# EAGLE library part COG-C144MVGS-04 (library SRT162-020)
1.5 inch LCD

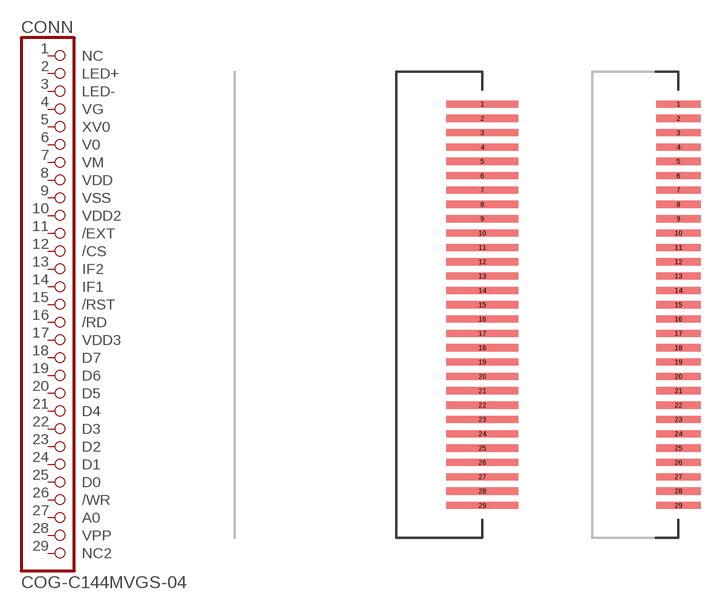
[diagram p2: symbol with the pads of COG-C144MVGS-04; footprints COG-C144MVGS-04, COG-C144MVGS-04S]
Designator prefix CONN

## COG-C144MVGS-04  [COG-C144MVGS-04]
1  NC  pas
2  LED+  pas
3  LED-  pas
4  VG  pas
5  XV0  pas
6  V0  pas
7  VM  pas
8  VDD  in
9  VSS  pas
10  VDD2  in
11  /EXT  pas
12  /CS  in
13  IF2  in
14  IF1  in
15  /RST  in
16  /RD  in
17  VDD3  in
18  D7
19  D6
20  D5
21  D4
22  D3
23  D2
24  D1
25  D0
26  /WR  in
27  A0  in
28  VPP  pas
29  NC2  pas

## COG-C144MVGS-04S  [COG-C144MVGS-04S]
1  NC  pas
2  LED-  pas
3  LED+  pas
4  VG  pas
5  XV0  pas
6  V0  pas
7  VM  pas
8  VDD  in
9  VSS  pas
10  VDD2  in
11  /EXT  pas
12  /CS  in
13  IF2  in
14  IF1  in
15  /RST  in
16  /RD  in
17  VDD3  in
18  D7
19  D6
20  D5
21  D4
22  D3
23  D2
24  D1
25  D0
26  /WR  in
27  A0  in
28  VPP  pas
29  NC2  pas

## Footprint COG-C144MVGS-04 (pad centres in mm)
COG-C144MVGS-04 : 1.5 inch LCD module
smd 4 x 0.4: 1 0,11.2; 2 0,10.4; 3 0,9.6; 4 0,8.8; 5 0,8; 6 0,7.2; 7 0,6.4; 8 0,5.6; 9 0,4.8; 10 0,4; 11 0,3.2; 12 0,2.4; 13 0,1.6; 14 0,0.8; 15 0,0; 16 0,-0.8; 17 0,-1.6; 18 0,-2.4; 19 0,-3.2; 20 0,-4; 21 0,-4.8; 22 0,-5.6; 23 0,-6.4; 24 0,-7.2; 25 0,-8; 26 0,-8.8; 27 0,-9.6; 28 0,-10.4; 29 0,-11.2

## Footprint COG-C144MVGS-04S (pad centres in mm)
smd 2.5 x 0.4: 1 0,11.2; 2 0,10.4; 3 0,9.6; 4 0,8.8; 5 0,8; 6 0,7.2; 7 0,6.4; 8 0,5.6; 9 0,4.8; 10 0,4; 11 0,3.2; 12 0,2.4; 13 0,1.6; 14 0,0.8; 15 0,0; 16 0,-0.8; 17 0,-1.6; 18 0,-2.4; 19 0,-3.2; 20 0,-4; 21 0,-4.8; 22 0,-5.6; 23 0,-6.4; 24 0,-7.2; 25 0,-8; 26 0,-8.8; 27 0,-9.6; 28 0,-10.4; 29 0,-11.2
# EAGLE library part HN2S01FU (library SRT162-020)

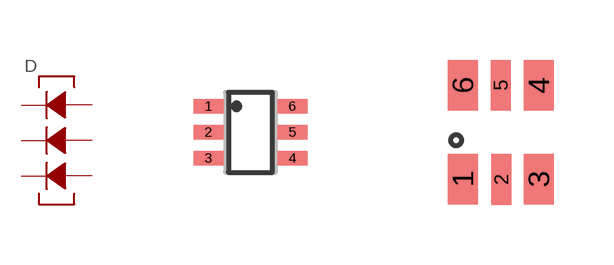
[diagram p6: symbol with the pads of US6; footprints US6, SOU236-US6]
Designator prefix D

## HN2S01FU  [US6]
1  1  pas
2  2  pas
3  3  pas
4  4  pas
5  5  pas
6  6  pas

## HN2S01FUL  [SOU236-US6]
Pads as for US6

## Footprint US6 (pad centres in mm)
0.65 mm pitch narrow (1.25 mm) width package
smd 0.762 x 0.356: 1 -1.05,0.65; 2 -1.05,0; 3 -1.05,-0.65; 4 1.05,-0.65; 5 1.05,0; 6 1.05,0.65

## Footprint SOU236-US6 (pad centres in mm)
smd 0.762 x 1.27: 1 -0.95,-1.175; 3 0.95,-1.175; 4 0.95,1.175; 6 -0.95,1.175
smd 0.508 x 1.27: 2 0.013,-1.185; 5 0,1.175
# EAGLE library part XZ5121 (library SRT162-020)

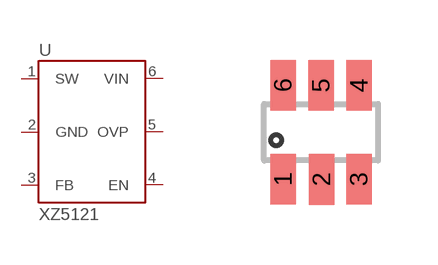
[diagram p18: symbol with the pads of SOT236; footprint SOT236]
Designator prefix U

## XZ5121  [SOT236]
1  SW  pas
2  GND  pwr
3  FB  in
4  EN  in
5  OVP  in
6  VIN  in

## Footprint SOT236 (pad centres in mm)
smd 0.635 x 1.27: 1 -0.95,-1.175; 2 0.013,-1.185; 3 0.95,-1.175; 4 0.95,1.175; 5 0,1.175; 6 -0.95,1.175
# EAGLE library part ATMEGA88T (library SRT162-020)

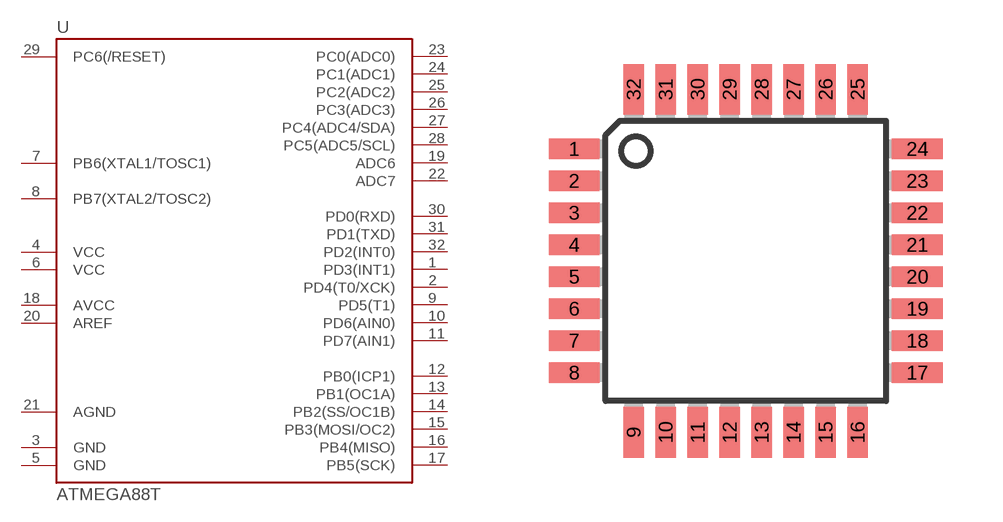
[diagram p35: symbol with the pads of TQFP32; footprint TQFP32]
Designator prefix U

## ATMEGA88T  [TQFP32]
1  PD3(INT1)
2  PD4(T0/XCK)
3  GND  pwr
4  VCC  pwr
5  GND  pwr
6  VCC  pwr
7  PB6(XTAL1/TOSC1)
8  PB7(XTAL2/TOSC2)
9  PD5(T1)
10  PD6(AIN0)
11  PD7(AIN1)
12  PB0(ICP1)
13  PB1(OC1A)
14  PB2(SS/OC1B)
15  PB3(MOSI/OC2)
16  PB4(MISO)
17  PB5(SCK)
18  AVCC  pas
19  ADC6  pas
20  AREF  pas
21  AGND  pwr
22  ADC7  pas
23  PC0(ADC0)
24  PC1(ADC1)
25  PC2(ADC2)
26  PC3(ADC3)
27  PC4(ADC4/SDA)
28  PC5(ADC5/SCL)
29  PC6(/RESET)
30  PD0(RXD)
31  PD1(TXD)
32  PD2(INT0)

## Footprint TQFP32 (pad centres in mm)
smd 1.27 x 0.508: 1 -4.293,2.8; 2 -4.293,2; 3 -4.293,1.2; 4 -4.293,0.4; 5 -4.293,-0.4; 6 -4.293,-1.2; 7 -4.293,-2; 8 -4.293,-2.8; 17 4.293,-2.8; 18 4.293,-2; 19 4.293,-1.2; 20 4.293,-0.4; 21 4.293,0.4; 22 4.293,1.2; 23 4.293,2; 24 4.293,2.8
smd 0.508 x 1.27: 9 -2.8,-4.293; 10 -2,-4.293; 11 -1.2,-4.293; 12 -0.4,-4.293; 13 0.4,-4.293; 14 1.2,-4.293; 15 2,-4.293; 16 2.8,-4.293; 25 2.8,4.293; 26 2,4.293; 27 1.2,4.293; 28 0.4,4.293; 29 -0.4,4.293; 30 -1.2,4.293; 31 -2,4.293; 32 -2.8,4.293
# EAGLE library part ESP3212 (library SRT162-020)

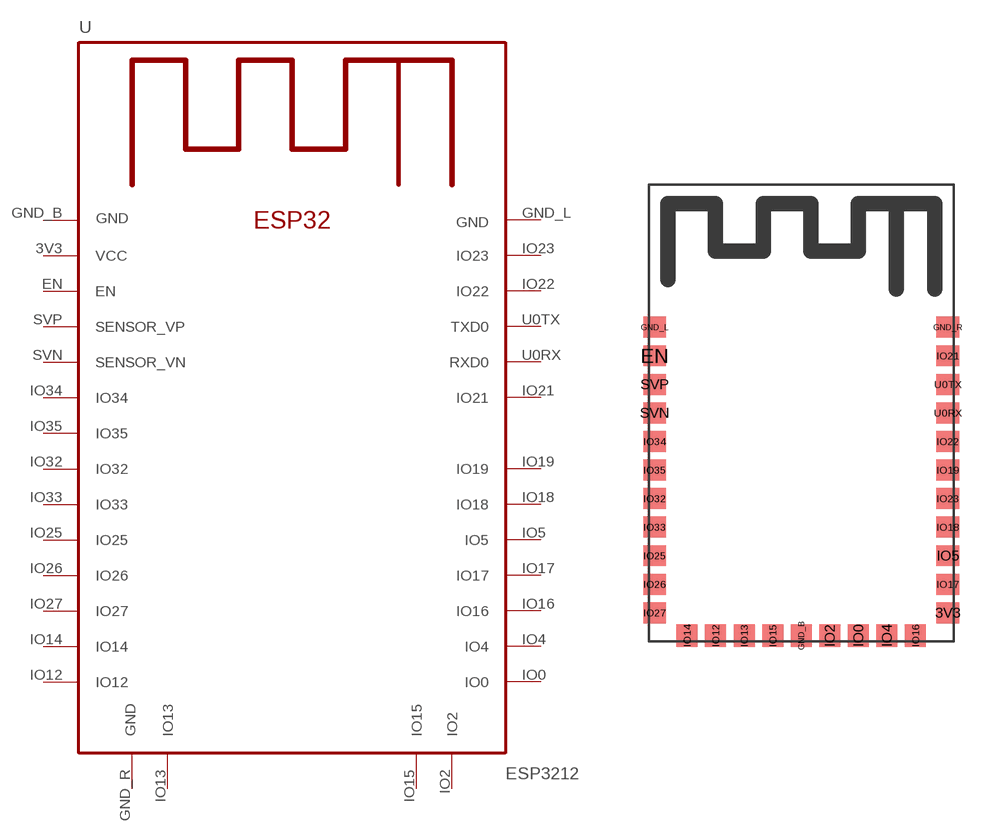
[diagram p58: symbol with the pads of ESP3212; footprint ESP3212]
Designator prefix U

## ESP3212  [ESP3212]
3V3  VCC  pwr
EN  EN
GND_B  GND  pwr
GND_L  GND  pwr
GND_R  GND  pwr
IO0  IO0
IO2  IO2
IO4  IO4
IO5  IO5
IO12  IO12
IO13  IO13
IO14  IO14
IO15  IO15
IO16  IO16
IO17  IO17
IO18  IO18
IO19  IO19
IO21  IO21
IO22  IO22
IO23  IO23
IO25  IO25
IO26  IO26
IO27  IO27
IO32  IO32
IO33  IO33
IO34  IO34
IO35  IO35
SVN  SENSOR_VN
SVP  SENSOR_VP
U0RX  RXD0
U0TX  TXD0

## Footprint ESP3212 (pad centres in mm)
smd 1.2 x 1.1: 3V3 8.08,-7.39; EN -7.32,6.11; GND_L -7.32,7.61; GND_R 8.08,7.61; IO5 8.08,-4.39; IO17 8.08,-5.89; IO18 8.08,-2.89; IO19 8.08,0.11; IO21 8.08,6.11; IO22 8.08,1.61; IO23 8.08,-1.39; IO25 -7.32,-4.39; IO26 -7.32,-5.89; IO27 -7.32,-7.39; IO32 -7.32,-1.39; IO33 -7.32,-2.89; IO34 -7.32,1.61; IO35 -7.32,0.11; SVN -7.32,3.11; SVP -7.32,4.61; U0RX 8.08,3.11; U0TX 8.08,4.61
smd 1.1 x 1.2: GND_B 0.38,-8.59; IO0 3.38,-8.59; IO2 1.88,-8.59; IO4 4.88,-8.59; IO12 -4.12,-8.59; IO13 -2.62,-8.59; IO14 -5.62,-8.59; IO15 -1.12,-8.59; IO16 6.38,-8.59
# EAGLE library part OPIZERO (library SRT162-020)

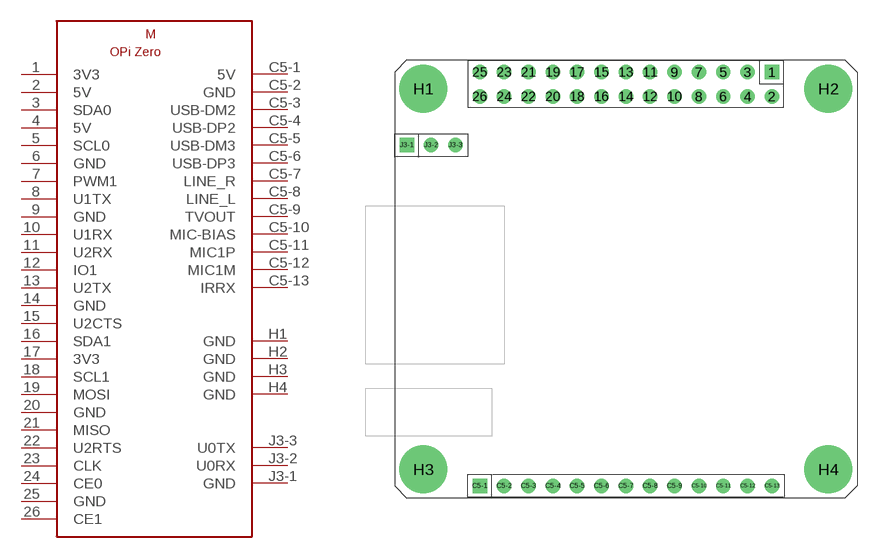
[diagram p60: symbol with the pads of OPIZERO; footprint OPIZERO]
Designator prefix M

## OPIZERO  [OPIZERO]
1  3V3
2  5V  pwr
3  SDA0
4  5V  pwr
5  SCL0
6  GND  pwr
7  PWM1
8  U1TX
9  GND  pwr
10  U1RX
11  U2RX
12  IO1
13  U2TX
14  GND  pwr
15  U2CTS
16  SDA1
17  3V3
18  SCL1
19  MOSI
20  GND  pwr
21  MISO
22  U2RTS
23  CLK
24  CE0
25  GND  pwr
26  CE1
C5-1  5V  pwr
C5-2  GND  pwr
C5-3  USB-DM2
C5-4  USB-DP2
C5-5  USB-DM3
C5-6  USB-DP3
C5-7  LINE_R
C5-8  LINE_L
C5-9  TVOUT
C5-10  MIC-BIAS
C5-11  MIC1P
C5-12  MIC1M
C5-13  IRRX
H1  GND  pwr
H2  GND  pwr
H3  GND  pwr
H4  GND  pwr
J3-1  GND  pwr
J3-2  U0RX
J3-3  U0TX

## Footprint OPIZERO (pad centres in mm)
drill 1 square: 1 15.24,22.86; C5-1 -15.24,-20.32; J3-1 -22.86,15.24
drill 1: 2 15.24,20.32; 3 12.7,22.86; 4 12.7,20.32; 5 10.16,22.86; 6 10.16,20.32; 7 7.62,22.86; 8 7.62,20.32; 9 5.08,22.86; 10 5.08,20.32; 11 2.54,22.86; 12 2.54,20.32; 13 0,22.86; 14 0,20.32; 15 -2.54,22.86; 16 -2.54,20.32; 17 -5.08,22.86; 18 -5.08,20.32; 19 -7.62,22.86; 20 -7.62,20.32; 21 -10.16,22.86; 22 -10.16,20.32; 23 -12.7,22.86; 24 -12.7,20.32; 25 -15.24,22.86; 26 -15.24,20.32; C5-2 -12.7,-20.32; C5-3 -10.16,-20.32; C5-4 -7.62,-20.32; C5-5 -5.08,-20.32; C5-6 -2.54,-20.32; C5-7 0,-20.32; C5-8 2.54,-20.32; C5-9 5.08,-20.32; C5-10 7.62,-20.32; C5-11 10.16,-20.32; C5-12 12.7,-20.32; C5-13 15.24,-20.32; J3-2 -20.32,15.24; J3-3 -17.78,15.24
drill 3.3 pad 5: H1 -21.13,21.13; H2 21.13,21.13; H3 -21.13,-18.59; H4 21.13,-18.59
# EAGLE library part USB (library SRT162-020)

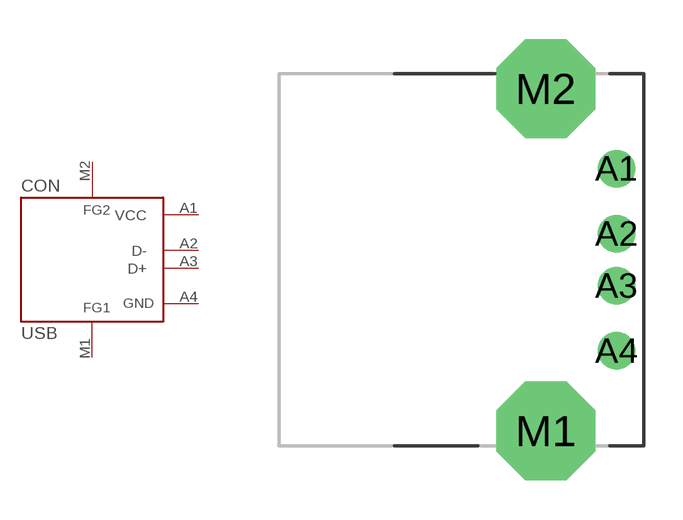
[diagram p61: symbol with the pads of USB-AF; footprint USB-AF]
Designator prefix CON

## USB-B  [USB-AF]
A1  VCC  pwr
A2  D-
A3  D+
A4  GND  pwr
M1  GND  pwr
M2  GND  pwr

## Footprint USB-AF (pad centres in mm)
drill 0.93: A1 3.175,3.5; A2 3.175,1; A3 3.175,-1; A4 3.175,-3.5
drill 2.4 pad 3.81 octagon: M1 0.465,-6.57; M2 0.465,6.57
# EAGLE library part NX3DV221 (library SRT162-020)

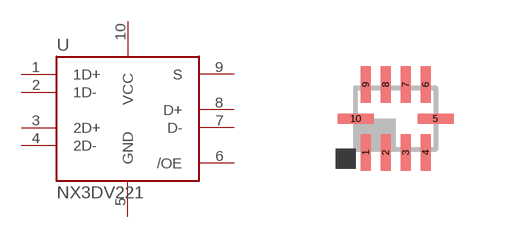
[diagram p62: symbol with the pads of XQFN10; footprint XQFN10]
Designator prefix -

## NX3DV221  [XQFN10]
1  1D+
2  1D-
3  2D+
4  2D-
5  GND  pwr
6  /OE
7  D-
8  D+
9  S
10  VCC  in

## Footprint XQFN10 (pad centres in mm)
smd 0.25 x 0.9: 1 -0.75,-0.85; 2 -0.25,-0.85; 3 0.25,-0.85; 4 0.75,-0.85; 6 0.75,0.85; 7 0.25,0.85; 8 -0.25,0.85; 9 -0.75,0.85
smd 0.9 x 0.25: 5 1,0; 10 -1,0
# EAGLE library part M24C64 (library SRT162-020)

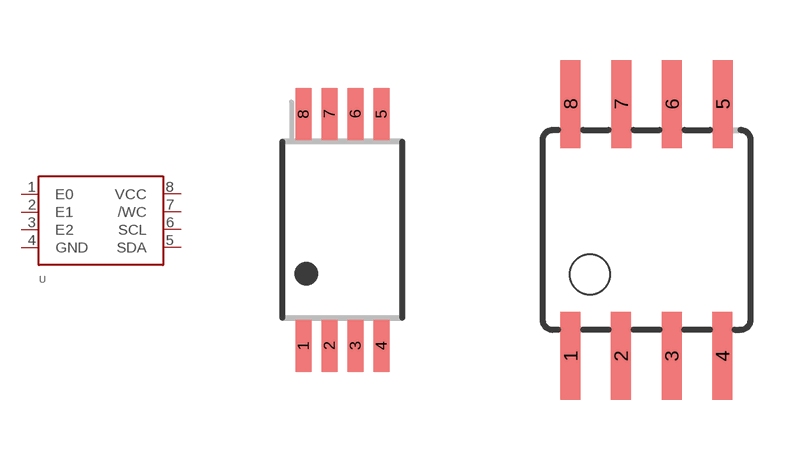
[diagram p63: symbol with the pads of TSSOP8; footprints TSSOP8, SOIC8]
Designator prefix -

## M24C64-DW  [TSSOP8]
1  E0  in
2  E1  in
3  E2  in
4  GND  pwr
5  SDA
6  SCL
7  /WC
8  VCC  pwr

## M24C64  [SOIC8]
Pads as for TSSOP8

## Footprint TSSOP8 (pad centres in mm)
smd 0.4 x 1.3: 1 -0.975,-2.9; 2 -0.325,-2.9; 3 0.325,-2.9; 4 0.975,-2.9; 5 0.975,2.9; 6 0.325,2.9; 7 -0.325,2.9; 8 -0.975,2.9

## Footprint SOIC8 (pad centres in mm)
smd 0.5 x 2.2: 1 -1.905,-3.154; 2 -0.645,-3.154; 3 0.625,-3.154; 4 1.895,-3.154; 5 1.905,3.154; 6 0.635,3.154; 7 -0.635,3.154; 8 -1.905,3.154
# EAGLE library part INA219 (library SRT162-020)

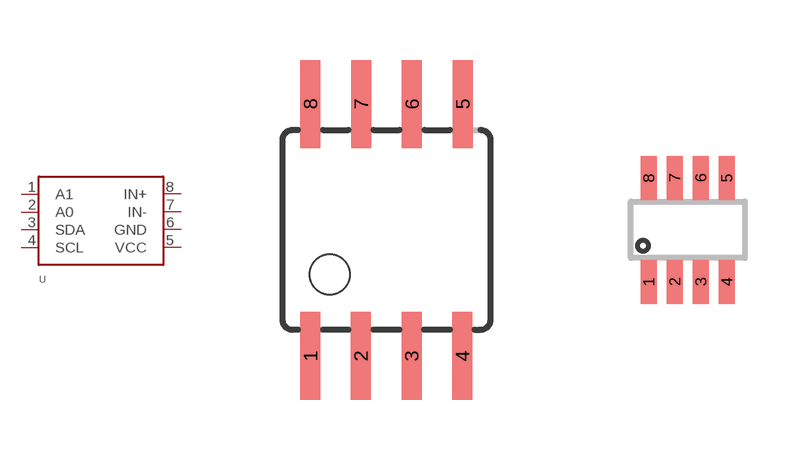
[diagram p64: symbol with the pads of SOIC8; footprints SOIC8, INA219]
Designator prefix -

## INA219SOP8  [SOIC8]
1  A1  in
2  A0  in
3  SDA
4  SCL
5  VCC  pwr
6  GND  pwr
7  IN-
8  IN+

## INA219SOT23-8  [INA219]
Pads as for SOIC8

## Footprint SOIC8 (pad centres in mm)
smd 0.5 x 2.2: 1 -1.905,-3.154; 2 -0.645,-3.154; 3 0.625,-3.154; 4 1.895,-3.154; 5 1.905,3.154; 6 0.635,3.154; 7 -0.635,3.154; 8 -1.905,3.154

## Footprint INA219 (pad centres in mm)
smd 0.4 x 1.1: 1 -0.975,-1.3; 2 -0.325,-1.3; 3 0.325,-1.3; 4 0.975,-1.3; 5 0.975,1.3; 6 0.325,1.3; 7 -0.325,1.3; 8 -0.975,1.3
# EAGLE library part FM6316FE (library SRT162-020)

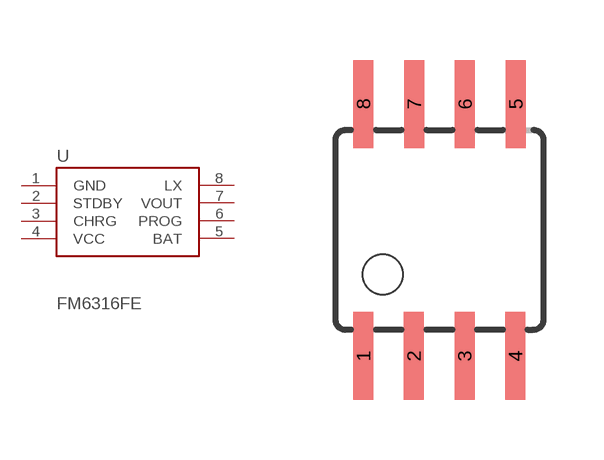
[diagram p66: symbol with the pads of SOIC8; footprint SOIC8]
Designator prefix -

## FM6316FE  [SOIC8]
1  GND  pwr
2  STDBY
3  CHRG
4  VCC
5  BAT
6  PROG
7  VOUT
8  LX

## Footprint SOIC8 (pad centres in mm)
smd 0.5 x 2.2: 1 -1.905,-3.154; 2 -0.645,-3.154; 3 0.625,-3.154; 4 1.895,-3.154; 5 1.905,3.154; 6 0.635,3.154; 7 -0.635,3.154; 8 -1.905,3.154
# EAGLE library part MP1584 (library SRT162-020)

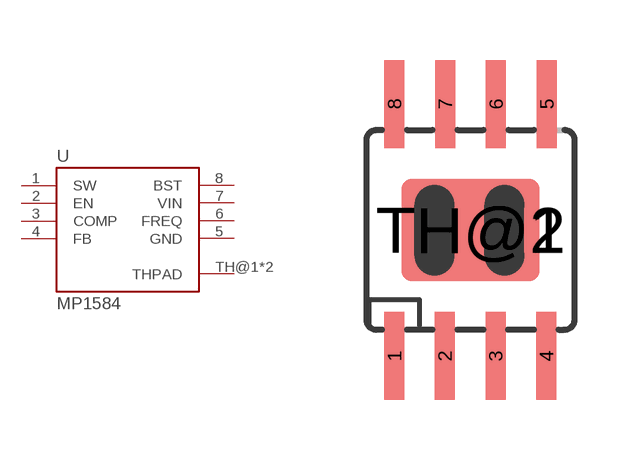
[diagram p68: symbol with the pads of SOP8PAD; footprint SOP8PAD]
Designator prefix -

## MP1584  [SOP8PAD]
1  SW
2  EN
3  COMP
4  FB
5  GND  pwr
6  FREQ
7  VIN
8  BST
TH@1  THPAD  pwr
TH@2  THPAD  pwr

## Footprint SOP8PAD (pad centres in mm)
smd 0.5 x 2.2: 1 -1.905,-3.154; 2 -0.645,-3.154; 3 0.625,-3.154; 4 1.895,-3.154; 5 1.905,3.154; 6 0.635,3.154; 7 -0.635,3.154; 8 -1.905,3.154
smd 3.454 x 2.565: TH@1 0,0
smd 3.454 x 2.565 bottom: TH@2 0,0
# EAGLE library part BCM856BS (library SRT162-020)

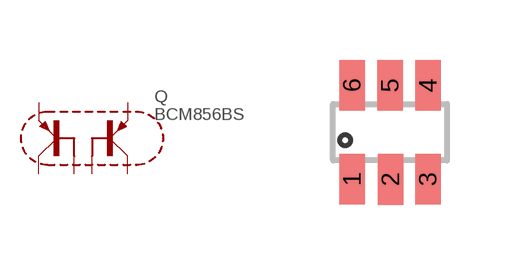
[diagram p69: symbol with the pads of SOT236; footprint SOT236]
Designator prefix Q

## BCM856BSSOT236  [SOT236]
1  E1  pas
2  B1  pas
3  C2  pas
4  E2  pas
5  B2  pas
6  C1  pas

## Footprint SOT236 (pad centres in mm)
smd 0.635 x 1.27: 1 -0.95,-1.175; 2 0.013,-1.185; 3 0.95,-1.175; 4 0.95,1.175; 5 0,1.175; 6 -0.95,1.175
